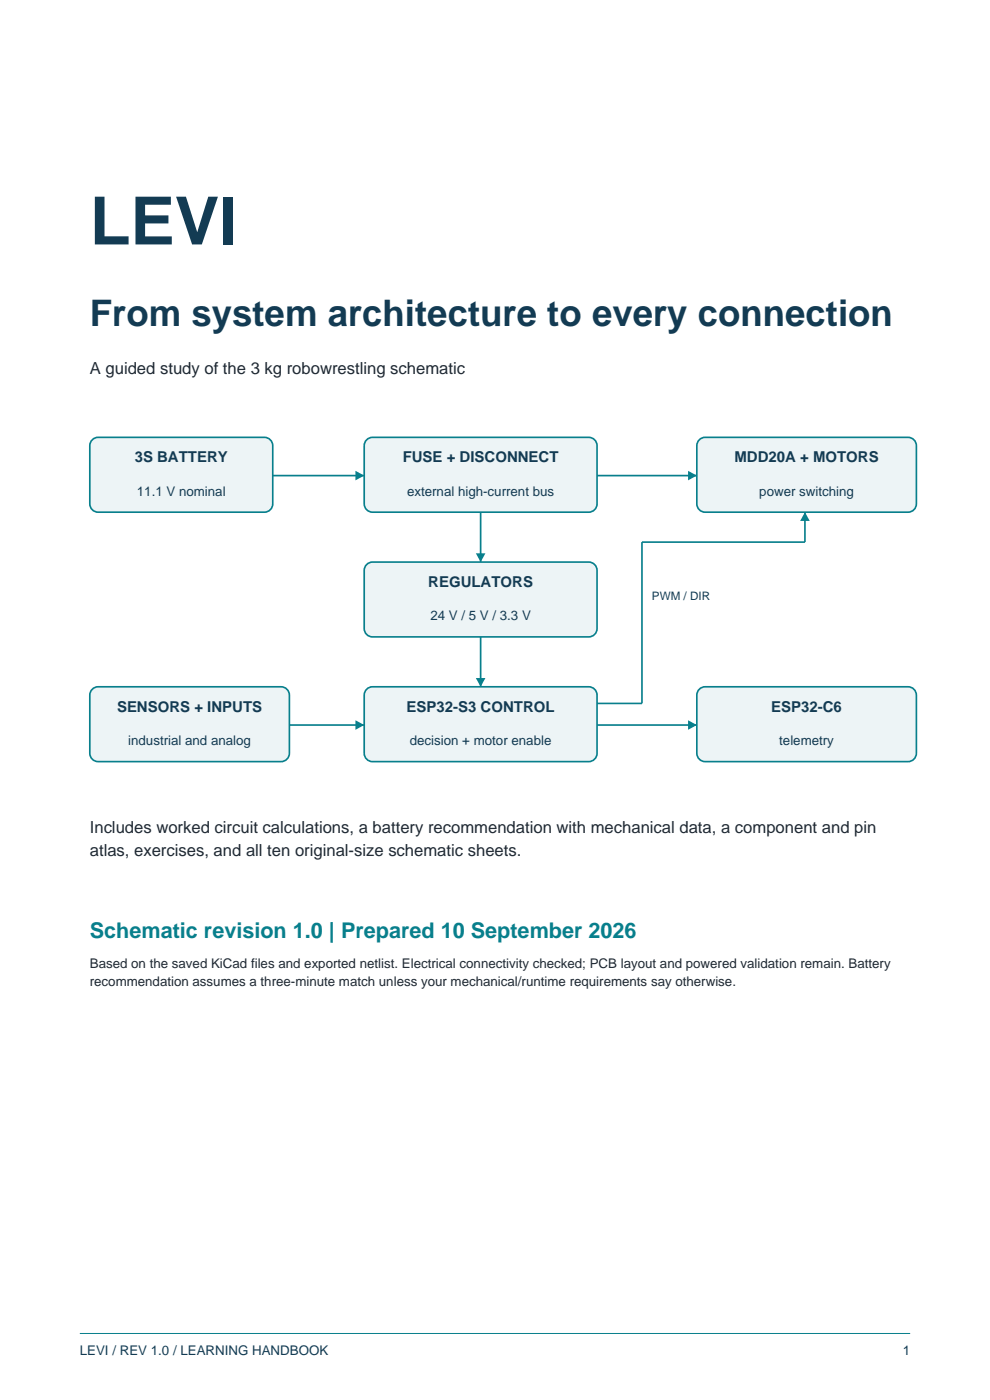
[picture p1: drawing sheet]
<svg xmlns="http://www.w3.org/2000/svg" width="210mm" height="297mm" viewBox="0 0 210 297" stroke-linecap="round" stroke-linejoin="round" font-family="sans-serif">
<defs><g id="words">
<text font-size="14.1" fill="#133b53" x="19" y="51.9">LEVI</text>
<text font-size="7.8" fill="#133b53" x="19" y="69.1">From system architecture to every connection</text>
<text font-size="4.6" fill="#087f8c" x="19" y="199">Schematic revision 1.0 | Prepared 10 September 2026</text>
<g font-size="3.5" fill="#1f2933">
<text x="19" y="79.4">A guided study of the 3 kg robowrestling schematic</text>
<text x="19" y="176.7">Includes worked circuit calculations, a battery recommendation with mechanical data, a component and pin</text>
<text x="19" y="181.7">atlas, exercises, and all ten original-size schematic sheets.</text>
</g>
<g font-size="3.2" fill="#133b53">
<text x="28.6" y="98.1">3S BATTERY</text>
<text x="85.4" y="98.1">FUSE + DISCONNECT</text>
<text x="155.8" y="98.1">MDD20A + MOTORS</text>
<text x="90.8" y="124.5">REGULATORS</text>
<text x="24.8" y="151">SENSORS + INPUTS</text>
<text x="86.3" y="151">ESP32-S3 CONTROL</text>
<text x="163.6" y="151">ESP32-C6</text>
</g>
<g font-size="2.8" fill="#133b53">
<text x="29" y="105.1">11.1 V nominal</text>
<text x="86.3" y="105.1">external high-current bus</text>
<text x="161.1" y="105.1">power switching</text>
<text x="91.3" y="131.6">24 V / 5 V / 3.3 V</text>
<text x="27.2" y="158">industrial and analog</text>
<text x="86.9" y="158">decision + motor enable</text>
<text x="165.3" y="158">telemetry</text>
<text x="16.9" y="287.5">LEVI / REV 1.0 / LEARNING HANDBOOK</text>
<text x="191.5" y="287.5">1</text>
</g>
<g font-size="2.8" fill="#1f2933">
<text x="19" y="205.3">Based on the saved KiCad files and exported netlist. Electrical connectivity checked; PCB layout and powered validation remain. Battery</text>
<text x="19" y="209.2">recommendation assumes a three-minute match unless your mechanical/runtime requirements say otherwise.</text>
</g>
<text font-size="2.5" fill="#133b53" x="138.3" y="127.4">PWM / DIR</text>
</g></defs>
<path d="M16.9 282.9h176.2" fill="none" stroke="#087f8c" stroke-width=".21"/>
<g fill="#edf4f6" stroke="#087f8c" stroke-width=".35">
<path d="M19.6 93.3l.7-.5h.5h35.3a1.76 1.76 0 0 1 1.8 1.7v12.4a1.76 1.76 0 0 1-1.8 1.8h-35.3a1.76 1.76 0 0 1-1.8-1.8v-12.4l.1-.4z" fill-rule="evenodd"/>
<path d="M77.8 93.3l.8-.5h.4h45.9a1.76 1.76 0 0 1 1.7 1.7v12.4a1.76 1.76 0 0 1-1.7 1.8h-45.9a1.76 1.76 0 0 1-1.7-1.8v-12.4v-.4z" fill-rule="evenodd"/>
<path d="M148.3 93.3l.8-.5h.5h43a1.76 1.76 0 0 1 1.8 1.7v12.4a1.76 1.76 0 0 1-1.8 1.8h-43a1.76 1.76 0 0 1-1.8-1.8v-12.4l.1-.4z" fill-rule="evenodd"/>
</g>
<path d="M57.9 100.9h19.4" fill="none" stroke="#087f8c" stroke-width=".35"/>
<path d="M75.4 99.9l1.9 1-1.9 1z" fill="#087f8c"/>
<path d="M126.6 100.9h21.2" fill="none" stroke="#087f8c" stroke-width=".35"/>
<path d="M146 99.9l1.8 1-1.8 1z" fill="#087f8c"/>
<path d="M77.8 119.8l.8-.5 .4-.1h45.9a1.76 1.76 0 0 1 1.7 1.8v12.3a1.76 1.76 0 0 1-1.7 1.8h-45.9a1.76 1.76 0 0 1-1.7-1.8v-12.3v-.5z" fill-rule="evenodd" fill="#edf4f6" stroke="#087f8c" stroke-width=".35"/>
<path d="M102 108.7v10.5" fill="none" stroke="#087f8c" stroke-width=".35"/>
<path d="M100.9 117.4h2.1l-1 1.8z" fill="#087f8c"/>
<g fill="#edf4f6" stroke="#087f8c" stroke-width=".35">
<path d="M19.6 146.2l.7-.4 .5-.1h38.8a1.76 1.76 0 0 1 1.8 1.8v12.3a1.76 1.76 0 0 1-1.8 1.8h-38.8a1.76 1.76 0 0 1-1.8-1.8v-12.3l.1-.5z" fill-rule="evenodd"/>
<path d="M77.8 146.2l.8-.4 .4-.1h45.9a1.76 1.76 0 0 1 1.7 1.8v12.3a1.76 1.76 0 0 1-1.7 1.8h-45.9a1.76 1.76 0 0 1-1.7-1.8v-12.3v-.5z" fill-rule="evenodd"/>
<path d="M148.3 146.2l.8-.4 .5-.1h43a1.76 1.76 0 0 1 1.8 1.8v12.3a1.76 1.76 0 0 1-1.8 1.8h-43a1.76 1.76 0 0 1-1.8-1.8v-12.3l.1-.5z" fill-rule="evenodd"/>
</g>
<path d="M61.4 153.8h15.9" fill="none" stroke="#087f8c" stroke-width=".35"/>
<path d="M75.4 152.8l1.9 1-1.9 1z" fill="#087f8c"/>
<path d="M126.6 153.8h21.2" fill="none" stroke="#087f8c" stroke-width=".35"/>
<path d="M146 152.8l1.8 1-1.8 1z" fill="#087f8c"/>
<path d="M102 135.1v10.6" fill="none" stroke="#087f8c" stroke-width=".35"/>
<path d="M100.9 143.8h2.1l-1 1.9z" fill="#087f8c"/>
<path d="M170.7 108.7v6.3h-34.5v34.2h-9.6" fill="none" stroke="#087f8c" stroke-width=".35"/>
<path d="M170.7 108.7l1.1 1.8h-2.1z" fill="#087f8c"/>
<use href="#words"/>
</svg>
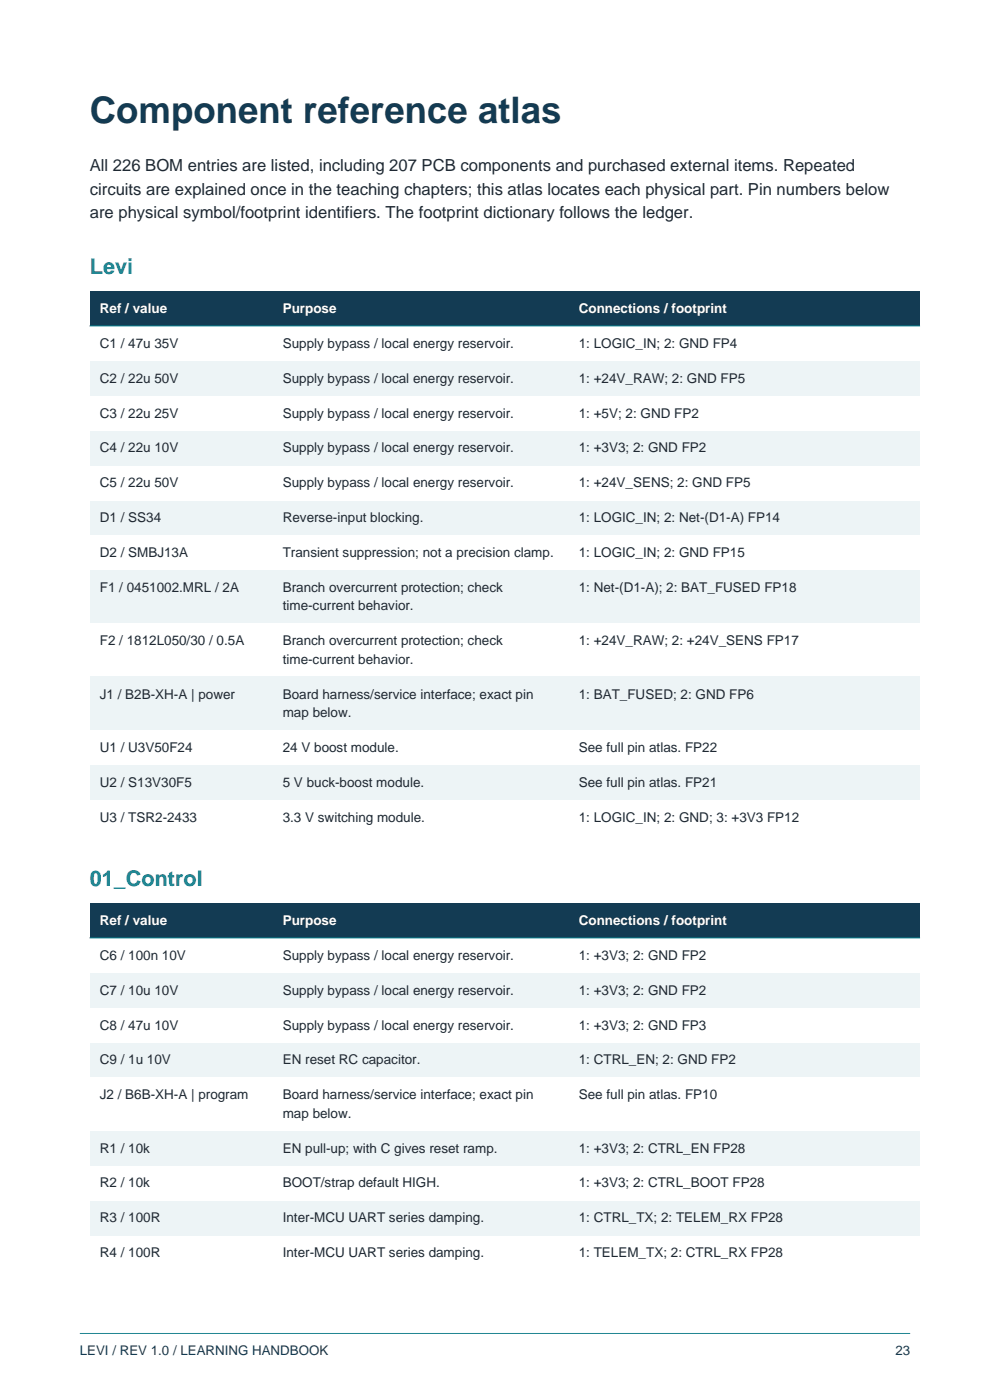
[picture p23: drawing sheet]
<svg xmlns="http://www.w3.org/2000/svg" width="210mm" height="297mm" viewBox="0 0 210 297" stroke-linecap="round" stroke-linejoin="round" font-family="sans-serif">
<defs><g id="words">
<text font-size="7.8" fill="#133b53" x="19" y="26.1">Component reference atlas</text>
<g font-size="4.6" fill="#087f8c">
<text x="19" y="58.2">Levi</text>
<text x="19" y="188">01_Control</text>
</g>
<g font-size="3.5" fill="#1f2933">
<text x="19" y="36.3">All 226 BOM entries are listed, including 207 PCB components and purchased external items. Repeated</text>
<text x="19" y="41.3">circuits are explained once in the teaching chapters; this atlas locates each physical part. Pin numbers below</text>
<text x="19" y="46.2">are physical symbol/footprint identifiers. The footprint dictionary follows the ledger.</text>
</g>
<g font-size="2.9" fill="#fff">
<text x="21.2" y="66.4">Ref / value</text>
<text x="60" y="66.4">Purpose</text>
<text x="122.8" y="66.4">Connections / footprint</text>
<text x="21.2" y="196.2">Ref / value</text>
<text x="60" y="196.2">Purpose</text>
<text x="122.8" y="196.2">Connections / footprint</text>
</g>
<g font-size="2.9" fill="#1f2933">
<text x="21.2" y="73.8">C1 / 47u 35V</text>
<text x="60" y="73.8">Supply bypass / local energy reservoir.</text>
<text x="122.8" y="73.8">1: LOGIC_IN; 2: GND FP4</text>
<text x="21.2" y="81.2">C2 / 22u 50V</text>
<text x="60" y="81.2">Supply bypass / local energy reservoir.</text>
<text x="122.8" y="81.2">1: +24V_RAW; 2: GND FP5</text>
<text x="21.2" y="88.6">C3 / 22u 25V</text>
<text x="60" y="88.6">Supply bypass / local energy reservoir.</text>
<text x="122.8" y="88.6">1: +5V; 2: GND FP2</text>
<text x="21.2" y="96">C4 / 22u 10V</text>
<text x="60" y="96">Supply bypass / local energy reservoir.</text>
<text x="122.8" y="96">1: +3V3; 2: GND FP2</text>
<text x="21.2" y="103.4">C5 / 22u 50V</text>
<text x="60" y="103.4">Supply bypass / local energy reservoir.</text>
<text x="122.8" y="103.4">1: +24V_SENS; 2: GND FP5</text>
<text x="21.2" y="110.8">D1 / SS34</text>
<text x="60" y="110.8">Reverse-input blocking.</text>
<text x="122.8" y="110.8">1: LOGIC_IN; 2: Net-(D1-A) FP14</text>
<text x="21.2" y="118.2">D2 / SMBJ13A</text>
<text x="60" y="118.2">Transient suppression; not a precision clamp.</text>
<text x="122.8" y="118.2">1: LOGIC_IN; 2: GND FP15</text>
<text x="21.2" y="125.6">F1 / 0451002.MRL / 2A</text>
<text x="60" y="125.6">Branch overcurrent protection; check</text>
<text x="122.8" y="125.6">1: Net-(D1-A); 2: BAT_FUSED FP18</text>
<text x="60" y="129.5">time-current behavior.</text>
<text x="21.2" y="136.9">F2 / 1812L050/30 / 0.5A</text>
<text x="60" y="136.9">Branch overcurrent protection; check</text>
<text x="122.8" y="136.9">1: +24V_RAW; 2: +24V_SENS FP17</text>
<text x="60" y="140.8">time-current behavior.</text>
<text x="21.2" y="148.2">J1 / B2B-XH-A | power</text>
<text x="60" y="148.2">Board harness/service interface; exact pin</text>
<text x="122.8" y="148.2">1: BAT_FUSED; 2: GND FP6</text>
<text x="60" y="152.1">map below.</text>
<text x="21.2" y="159.5">U1 / U3V50F24</text>
<text x="60" y="159.5">24 V boost module.</text>
<text x="122.8" y="159.5">See full pin atlas. FP22</text>
<text x="21.2" y="166.9">U2 / S13V30F5</text>
<text x="60" y="166.9">5 V buck-boost module.</text>
<text x="122.8" y="166.9">See full pin atlas. FP21</text>
<text x="21.2" y="174.3">U3 / TSR2-2433</text>
<text x="60" y="174.3">3.3 V switching module.</text>
<text x="122.8" y="174.3">1: LOGIC_IN; 2: GND; 3: +3V3 FP12</text>
<text x="21.2" y="203.6">C6 / 100n 10V</text>
<text x="60" y="203.6">Supply bypass / local energy reservoir.</text>
<text x="122.8" y="203.6">1: +3V3; 2: GND FP2</text>
<text x="21.2" y="211">C7 / 10u 10V</text>
<text x="60" y="211">Supply bypass / local energy reservoir.</text>
<text x="122.8" y="211">1: +3V3; 2: GND FP2</text>
<text x="21.2" y="218.4">C8 / 47u 10V</text>
<text x="60" y="218.4">Supply bypass / local energy reservoir.</text>
<text x="122.8" y="218.4">1: +3V3; 2: GND FP3</text>
<text x="21.2" y="225.8">C9 / 1u 10V</text>
<text x="60" y="225.8">EN reset RC capacitor.</text>
<text x="122.8" y="225.8">1: CTRL_EN; 2: GND FP2</text>
<text x="21.2" y="233.2">J2 / B6B-XH-A | program</text>
<text x="60" y="233.2">Board harness/service interface; exact pin</text>
<text x="122.8" y="233.2">See full pin atlas. FP10</text>
<text x="60" y="237.1">map below.</text>
<text x="21.2" y="244.5">R1 / 10k</text>
<text x="60" y="244.5">EN pull-up; with C gives reset ramp.</text>
<text x="122.8" y="244.5">1: +3V3; 2: CTRL_EN FP28</text>
<text x="21.2" y="251.9">R2 / 10k</text>
<text x="60" y="251.9">BOOT/strap default HIGH.</text>
<text x="122.8" y="251.9">1: +3V3; 2: CTRL_BOOT FP28</text>
<text x="21.2" y="259.3">R3 / 100R</text>
<text x="60" y="259.3">Inter-MCU UART series damping.</text>
<text x="122.8" y="259.3">1: CTRL_TX; 2: TELEM_RX FP28</text>
<text x="21.2" y="266.7">R4 / 100R</text>
<text x="60" y="266.7">Inter-MCU UART series damping.</text>
<text x="122.8" y="266.7">1: TELEM_TX; 2: CTRL_RX FP28</text>
</g>
<g font-size="2.8" fill="#133b53">
<text x="16.9" y="287.5">LEVI / REV 1.0 / LEARNING HANDBOOK</text>
<text x="189.9" y="287.5">23</text>
</g>
</g></defs>
<path d="M16.9 282.9h176.2" fill="none" stroke="#087f8c" stroke-width=".21"/>
<path d="M19 61.7h176.1v7.4h-176.1z" fill-rule="evenodd" fill="#133b53"/>
<path d="M19 69.1h176.1v7.5h-176.1z" fill-rule="evenodd" fill="#fff"/>
<path d="M19 76.6h176.1v7.4h-176.1z" fill-rule="evenodd" fill="#edf4f6"/>
<path d="M19 84h176.1v7.4h-176.1z" fill-rule="evenodd" fill="#fff"/>
<path d="M19 91.4h176.1v7.4h-176.1z" fill-rule="evenodd" fill="#edf4f6"/>
<path d="M19 98.8h176.1v7.4h-176.1z" fill-rule="evenodd" fill="#fff"/>
<path d="M19 106.2h176.1v7.4h-176.1z" fill-rule="evenodd" fill="#edf4f6"/>
<path d="M19 113.6h176.1v7.4h-176.1z" fill-rule="evenodd" fill="#fff"/>
<path d="M19 121h176.1v11.3h-176.1z" fill-rule="evenodd" fill="#edf4f6"/>
<path d="M19 132.3h176.1v11.3h-176.1z" fill-rule="evenodd" fill="#fff"/>
<path d="M19 143.6h176.1v11.3h-176.1z" fill-rule="evenodd" fill="#edf4f6"/>
<path d="M19 154.9h176.1v7.4h-176.1z" fill-rule="evenodd" fill="#fff"/>
<path d="M19 162.3h176.1v7.4h-176.1z" fill-rule="evenodd" fill="#edf4f6"/>
<path d="M19 169.7h176.1v7.4h-176.1z" fill-rule="evenodd" fill="#fff"/>
<path d="M19 69.1h176.1" fill="none" stroke="#087f8c" stroke-width=".21"/>
<path d="M19 191.6h176.1v7.4h-176.1z" fill-rule="evenodd" fill="#133b53"/>
<path d="M19 199h176.1v7.4h-176.1z" fill-rule="evenodd" fill="#fff"/>
<path d="M19 206.4h176.1v7.4h-176.1z" fill-rule="evenodd" fill="#edf4f6"/>
<path d="M19 213.8h176.1v7.4h-176.1z" fill-rule="evenodd" fill="#fff"/>
<path d="M19 221.2h176.1v7.4h-176.1z" fill-rule="evenodd" fill="#edf4f6"/>
<path d="M19 228.6h176.1v11.3h-176.1z" fill-rule="evenodd" fill="#fff"/>
<path d="M19 239.9h176.1v7.4h-176.1z" fill-rule="evenodd" fill="#edf4f6"/>
<path d="M19 247.3h176.1v7.4h-176.1z" fill-rule="evenodd" fill="#fff"/>
<path d="M19 254.7h176.1v7.4h-176.1z" fill-rule="evenodd" fill="#edf4f6"/>
<path d="M19 262.1h176.1v7.4h-176.1z" fill-rule="evenodd" fill="#fff"/>
<path d="M19 199h176.1" fill="none" stroke="#087f8c" stroke-width=".21"/>
<use href="#words"/>
</svg>
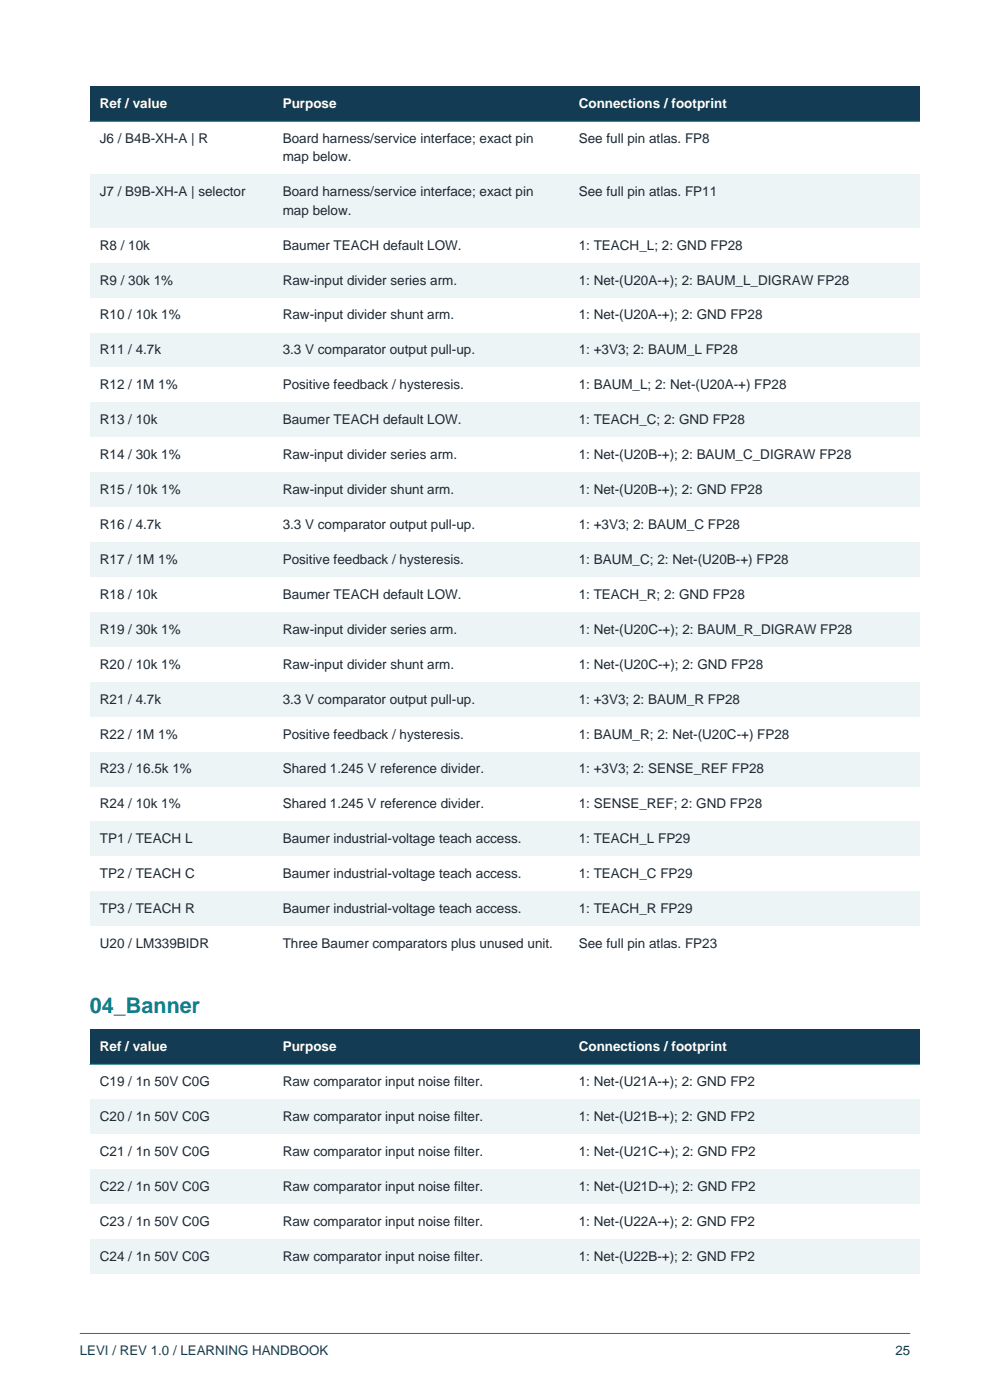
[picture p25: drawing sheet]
<svg xmlns="http://www.w3.org/2000/svg" width="210mm" height="297mm" viewBox="0 0 210 297" stroke-linecap="round" stroke-linejoin="round" font-family="sans-serif">
<defs><g id="words">
<text font-size="4.6" fill="#087f8c" x="19" y="214.8">04_Banner</text>
<g font-size="2.9" fill="#fff">
<text x="21.2" y="23">Ref / value</text>
<text x="60" y="23">Purpose</text>
<text x="122.8" y="23">Connections / footprint</text>
<text x="21.2" y="223">Ref / value</text>
<text x="60" y="223">Purpose</text>
<text x="122.8" y="223">Connections / footprint</text>
</g>
<g font-size="2.9" fill="#1f2933">
<text x="21.2" y="30.4">J6 / B4B-XH-A | R</text>
<text x="60" y="30.4">Board harness/service interface; exact pin</text>
<text x="60" y="34.3">map below.</text>
<text x="122.8" y="30.4">See full pin atlas. FP8</text>
<text x="21.2" y="41.7">J7 / B9B-XH-A | selector</text>
<text x="60" y="41.7">Board harness/service interface; exact pin</text>
<text x="122.8" y="41.7">See full pin atlas. FP11</text>
<text x="60" y="45.5">map below.</text>
<text x="21.2" y="53">R8 / 10k</text>
<text x="60" y="53">Baumer TEACH default LOW.</text>
<text x="122.8" y="53">1: TEACH_L; 2: GND FP28</text>
<text x="21.2" y="60.4">R9 / 30k 1%</text>
<text x="60" y="60.4">Raw-input divider series arm.</text>
<text x="122.8" y="60.4">1: Net-(U20A-+); 2: BAUM_L_DIGRAW FP28</text>
<text x="21.2" y="67.8">R10 / 10k 1%</text>
<text x="60" y="67.8">Raw-input divider shunt arm.</text>
<text x="122.8" y="67.8">1: Net-(U20A-+); 2: GND FP28</text>
<text x="21.2" y="75.2">R11 / 4.7k</text>
<text x="60" y="75.2">3.3 V comparator output pull-up.</text>
<text x="122.8" y="75.2">1: +3V3; 2: BAUM_L FP28</text>
<text x="21.2" y="82.6">R12 / 1M 1%</text>
<text x="60" y="82.6">Positive feedback / hysteresis.</text>
<text x="122.8" y="82.6">1: BAUM_L; 2: Net-(U20A-+) FP28</text>
<text x="21.2" y="90">R13 / 10k</text>
<text x="60" y="90">Baumer TEACH default LOW.</text>
<text x="122.8" y="90">1: TEACH_C; 2: GND FP28</text>
<text x="21.2" y="97.4">R14 / 30k 1%</text>
<text x="60" y="97.4">Raw-input divider series arm.</text>
<text x="122.8" y="97.4">1: Net-(U20B-+); 2: BAUM_C_DIGRAW FP28</text>
<text x="21.2" y="104.8">R15 / 10k 1%</text>
<text x="60" y="104.8">Raw-input divider shunt arm.</text>
<text x="122.8" y="104.8">1: Net-(U20B-+); 2: GND FP28</text>
<text x="21.2" y="112.2">R16 / 4.7k</text>
<text x="60" y="112.2">3.3 V comparator output pull-up.</text>
<text x="122.8" y="112.2">1: +3V3; 2: BAUM_C FP28</text>
<text x="21.2" y="119.6">R17 / 1M 1%</text>
<text x="60" y="119.6">Positive feedback / hysteresis.</text>
<text x="122.8" y="119.6">1: BAUM_C; 2: Net-(U20B-+) FP28</text>
<text x="21.2" y="127">R18 / 10k</text>
<text x="60" y="127">Baumer TEACH default LOW.</text>
<text x="122.8" y="127">1: TEACH_R; 2: GND FP28</text>
<text x="21.2" y="134.4">R19 / 30k 1%</text>
<text x="60" y="134.4">Raw-input divider series arm.</text>
<text x="122.8" y="134.4">1: Net-(U20C-+); 2: BAUM_R_DIGRAW FP28</text>
<text x="21.2" y="141.9">R20 / 10k 1%</text>
<text x="60" y="141.9">Raw-input divider shunt arm.</text>
<text x="122.8" y="141.9">1: Net-(U20C-+); 2: GND FP28</text>
<text x="21.2" y="149.3">R21 / 4.7k</text>
<text x="60" y="149.3">3.3 V comparator output pull-up.</text>
<text x="122.8" y="149.3">1: +3V3; 2: BAUM_R FP28</text>
<text x="21.2" y="156.7">R22 / 1M 1%</text>
<text x="60" y="156.7">Positive feedback / hysteresis.</text>
<text x="122.8" y="156.7">1: BAUM_R; 2: Net-(U20C-+) FP28</text>
<text x="21.2" y="164.1">R23 / 16.5k 1%</text>
<text x="60" y="164.1">Shared 1.245 V reference divider.</text>
<text x="122.8" y="164.1">1: +3V3; 2: SENSE_REF FP28</text>
<text x="21.2" y="171.5">R24 / 10k 1%</text>
<text x="60" y="171.5">Shared 1.245 V reference divider.</text>
<text x="122.8" y="171.5">1: SENSE_REF; 2: GND FP28</text>
<text x="21.2" y="178.9">TP1 / TEACH L</text>
<text x="60" y="178.9">Baumer industrial-voltage teach access.</text>
<text x="122.8" y="178.9">1: TEACH_L FP29</text>
<text x="21.2" y="186.3">TP2 / TEACH C</text>
<text x="60" y="186.3">Baumer industrial-voltage teach access.</text>
<text x="122.8" y="186.3">1: TEACH_C FP29</text>
<text x="21.2" y="193.7">TP3 / TEACH R</text>
<text x="60" y="193.7">Baumer industrial-voltage teach access.</text>
<text x="122.8" y="193.7">1: TEACH_R FP29</text>
<text x="21.2" y="201.1">U20 / LM339BIDR</text>
<text x="60" y="201.1">Three Baumer comparators plus unused unit.</text>
<text x="122.8" y="201.1">See full pin atlas. FP23</text>
<text x="21.2" y="230.4">C19 / 1n 50V C0G</text>
<text x="60" y="230.4">Raw comparator input noise filter.</text>
<text x="122.8" y="230.4">1: Net-(U21A-+); 2: GND FP2</text>
<text x="21.2" y="237.8">C20 / 1n 50V C0G</text>
<text x="60" y="237.8">Raw comparator input noise filter.</text>
<text x="122.8" y="237.8">1: Net-(U21B-+); 2: GND FP2</text>
<text x="21.2" y="245.2">C21 / 1n 50V C0G</text>
<text x="60" y="245.2">Raw comparator input noise filter.</text>
<text x="122.8" y="245.2">1: Net-(U21C-+); 2: GND FP2</text>
<text x="21.2" y="252.6">C22 / 1n 50V C0G</text>
<text x="60" y="252.6">Raw comparator input noise filter.</text>
<text x="122.8" y="252.6">1: Net-(U21D-+); 2: GND FP2</text>
<text x="21.2" y="260">C23 / 1n 50V C0G</text>
<text x="60" y="260">Raw comparator input noise filter.</text>
<text x="122.8" y="260">1: Net-(U22A-+); 2: GND FP2</text>
<text x="21.2" y="267.4">C24 / 1n 50V C0G</text>
<text x="60" y="267.4">Raw comparator input noise filter.</text>
<text x="122.8" y="267.4">1: Net-(U22B-+); 2: GND FP2</text>
</g>
<g font-size="2.8" fill="#133b53">
<text x="16.9" y="287.5">LEVI / REV 1.0 / LEARNING HANDBOOK</text>
<text x="189.9" y="287.5">25</text>
</g>
</g></defs>
<path d="M16.9 282.9h176.2" fill="none" stroke="#087f8c" stroke-width=".21"/>
<path d="M19 18.3h176.1v7.5h-176.1z" fill-rule="evenodd" fill="#133b53"/>
<path d="M19 25.8h176.1v11.2h-176.1z" fill-rule="evenodd" fill="#fff"/>
<path d="M19 37h176.1v11.3h-176.1z" fill-rule="evenodd" fill="#edf4f6"/>
<path d="M19 48.3h176.1v7.4h-176.1z" fill-rule="evenodd" fill="#fff"/>
<path d="M19 55.7h176.1v7.4h-176.1z" fill-rule="evenodd" fill="#edf4f6"/>
<path d="M19 63.1h176.1v7.5h-176.1z" fill-rule="evenodd" fill="#fff"/>
<path d="M19 70.6h176.1v7.4h-176.1z" fill-rule="evenodd" fill="#edf4f6"/>
<path d="M19 78h176.1v7.4h-176.1z" fill-rule="evenodd" fill="#fff"/>
<path d="M19 85.4h176.1v7.4h-176.1z" fill-rule="evenodd" fill="#edf4f6"/>
<path d="M19 92.8h176.1v7.4h-176.1z" fill-rule="evenodd" fill="#fff"/>
<path d="M19 100.2h176.1v7.4h-176.1z" fill-rule="evenodd" fill="#edf4f6"/>
<path d="M19 107.6h176.1v7.4h-176.1z" fill-rule="evenodd" fill="#fff"/>
<path d="M19 115h176.1v7.4h-176.1z" fill-rule="evenodd" fill="#edf4f6"/>
<path d="M19 122.4h176.1v7.4h-176.1z" fill-rule="evenodd" fill="#fff"/>
<path d="M19 129.8h176.1v7.4h-176.1z" fill-rule="evenodd" fill="#edf4f6"/>
<path d="M19 137.2h176.1v7.4h-176.1z" fill-rule="evenodd" fill="#fff"/>
<path d="M19 144.6h176.1v7.4h-176.1z" fill-rule="evenodd" fill="#edf4f6"/>
<path d="M19 152h176.1v7.5h-176.1z" fill-rule="evenodd" fill="#fff"/>
<path d="M19 159.5h176.1v7.4h-176.1z" fill-rule="evenodd" fill="#edf4f6"/>
<path d="M19 166.9h176.1v7.4h-176.1z" fill-rule="evenodd" fill="#fff"/>
<path d="M19 174.3h176.1v7.4h-176.1z" fill-rule="evenodd" fill="#edf4f6"/>
<path d="M19 181.7h176.1v7.4h-176.1z" fill-rule="evenodd" fill="#fff"/>
<path d="M19 189.1h176.1v7.4h-176.1z" fill-rule="evenodd" fill="#edf4f6"/>
<path d="M19 196.5h176.1v7.4h-176.1z" fill-rule="evenodd" fill="#fff"/>
<path d="M19 25.8h176.1" fill="none" stroke="#087f8c" stroke-width=".21"/>
<path d="M19 218.4h176.1v7.4h-176.1z" fill-rule="evenodd" fill="#133b53"/>
<path d="M19 225.8h176.1v7.4h-176.1z" fill-rule="evenodd" fill="#fff"/>
<path d="M19 233.2h176.1v7.4h-176.1z" fill-rule="evenodd" fill="#edf4f6"/>
<path d="M19 240.6h176.1v7.4h-176.1z" fill-rule="evenodd" fill="#fff"/>
<path d="M19 248h176.1v7.4h-176.1z" fill-rule="evenodd" fill="#edf4f6"/>
<path d="M19 255.4h176.1v7.4h-176.1z" fill-rule="evenodd" fill="#fff"/>
<path d="M19 262.8h176.1v7.4h-176.1z" fill-rule="evenodd" fill="#edf4f6"/>
<path d="M19 225.8h176.1" fill="none" stroke="#087f8c" stroke-width=".21"/>
<use href="#words"/>
</svg>
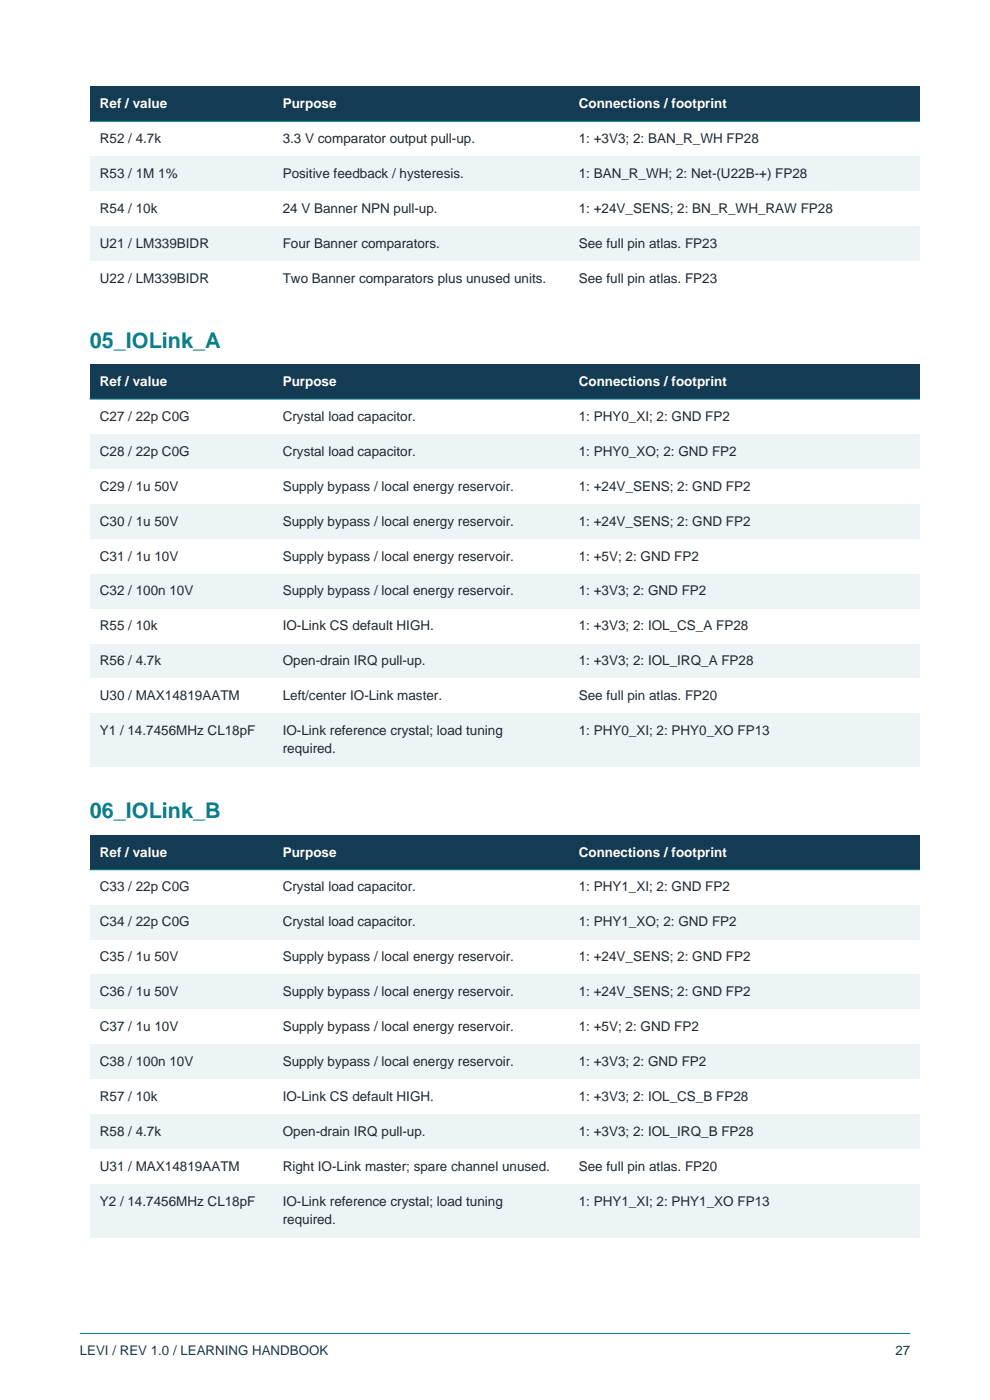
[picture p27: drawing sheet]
<svg xmlns="http://www.w3.org/2000/svg" width="210mm" height="297mm" viewBox="0 0 210 297" stroke-linecap="round" stroke-linejoin="round" font-family="sans-serif">
<defs><g id="words">
<g font-size="4.6" fill="#087f8c">
<text x="19" y="73.7">05_IOLink_A</text>
<text x="19" y="173.6">06_IOLink_B</text>
</g>
<g font-size="2.9" fill="#fff">
<text x="21.2" y="23">Ref / value</text>
<text x="60" y="23">Purpose</text>
<text x="122.8" y="23">Connections / footprint</text>
<text x="21.2" y="81.9">Ref / value</text>
<text x="60" y="81.9">Purpose</text>
<text x="122.8" y="81.9">Connections / footprint</text>
<text x="21.2" y="181.7">Ref / value</text>
<text x="60" y="181.7">Purpose</text>
<text x="122.8" y="181.7">Connections / footprint</text>
</g>
<g font-size="2.9" fill="#1f2933">
<text x="21.2" y="30.4">R52 / 4.7k</text>
<text x="60" y="30.4">3.3 V comparator output pull-up.</text>
<text x="122.8" y="30.4">1: +3V3; 2: BAN_R_WH FP28</text>
<text x="21.2" y="37.8">R53 / 1M 1%</text>
<text x="60" y="37.8">Positive feedback / hysteresis.</text>
<text x="122.8" y="37.8">1: BAN_R_WH; 2: Net-(U22B-+) FP28</text>
<text x="21.2" y="45.2">R54 / 10k</text>
<text x="60" y="45.2">24 V Banner NPN pull-up.</text>
<text x="122.8" y="45.2">1: +24V_SENS; 2: BN_R_WH_RAW FP28</text>
<text x="21.2" y="52.6">U21 / LM339BIDR</text>
<text x="60" y="52.6">Four Banner comparators.</text>
<text x="122.8" y="52.6">See full pin atlas. FP23</text>
<text x="21.2" y="60">U22 / LM339BIDR</text>
<text x="60" y="60">Two Banner comparators plus unused units.</text>
<text x="122.8" y="60">See full pin atlas. FP23</text>
<text x="21.2" y="89.3">C27 / 22p C0G</text>
<text x="60" y="89.3">Crystal load capacitor.</text>
<text x="122.8" y="89.3">1: PHY0_XI; 2: GND FP2</text>
<text x="21.2" y="96.7">C28 / 22p C0G</text>
<text x="60" y="96.7">Crystal load capacitor.</text>
<text x="122.8" y="96.7">1: PHY0_XO; 2: GND FP2</text>
<text x="21.2" y="104.1">C29 / 1u 50V</text>
<text x="60" y="104.1">Supply bypass / local energy reservoir.</text>
<text x="122.8" y="104.1">1: +24V_SENS; 2: GND FP2</text>
<text x="21.2" y="111.5">C30 / 1u 50V</text>
<text x="60" y="111.5">Supply bypass / local energy reservoir.</text>
<text x="122.8" y="111.5">1: +24V_SENS; 2: GND FP2</text>
<text x="21.2" y="118.9">C31 / 1u 10V</text>
<text x="60" y="118.9">Supply bypass / local energy reservoir.</text>
<text x="122.8" y="118.9">1: +5V; 2: GND FP2</text>
<text x="21.2" y="126.3">C32 / 100n 10V</text>
<text x="60" y="126.3">Supply bypass / local energy reservoir.</text>
<text x="122.8" y="126.3">1: +3V3; 2: GND FP2</text>
<text x="21.2" y="133.7">R55 / 10k</text>
<text x="60" y="133.7">IO-Link CS default HIGH.</text>
<text x="122.8" y="133.7">1: +3V3; 2: IOL_CS_A FP28</text>
<text x="21.2" y="141.1">R56 / 4.7k</text>
<text x="60" y="141.1">Open-drain IRQ pull-up.</text>
<text x="122.8" y="141.1">1: +3V3; 2: IOL_IRQ_A FP28</text>
<text x="21.2" y="148.6">U30 / MAX14819AATM</text>
<text x="60" y="148.6">Left/center IO-Link master.</text>
<text x="122.8" y="148.6">See full pin atlas. FP20</text>
<text x="21.2" y="156">Y1 / 14.7456MHz CL18pF</text>
<text x="60" y="156">IO-Link reference crystal; load tuning</text>
<text x="122.8" y="156">1: PHY0_XI; 2: PHY0_XO FP13</text>
<text x="60" y="159.8">required.</text>
<text x="21.2" y="189.1">C33 / 22p C0G</text>
<text x="60" y="189.1">Crystal load capacitor.</text>
<text x="122.8" y="189.1">1: PHY1_XI; 2: GND FP2</text>
<text x="21.2" y="196.5">C34 / 22p C0G</text>
<text x="60" y="196.5">Crystal load capacitor.</text>
<text x="122.8" y="196.5">1: PHY1_XO; 2: GND FP2</text>
<text x="21.2" y="203.9">C35 / 1u 50V</text>
<text x="60" y="203.9">Supply bypass / local energy reservoir.</text>
<text x="122.8" y="203.9">1: +24V_SENS; 2: GND FP2</text>
<text x="21.2" y="211.3">C36 / 1u 50V</text>
<text x="60" y="211.3">Supply bypass / local energy reservoir.</text>
<text x="122.8" y="211.3">1: +24V_SENS; 2: GND FP2</text>
<text x="21.2" y="218.8">C37 / 1u 10V</text>
<text x="60" y="218.8">Supply bypass / local energy reservoir.</text>
<text x="122.8" y="218.8">1: +5V; 2: GND FP2</text>
<text x="21.2" y="226.2">C38 / 100n 10V</text>
<text x="60" y="226.2">Supply bypass / local energy reservoir.</text>
<text x="122.8" y="226.2">1: +3V3; 2: GND FP2</text>
<text x="21.2" y="233.6">R57 / 10k</text>
<text x="60" y="233.6">IO-Link CS default HIGH.</text>
<text x="122.8" y="233.6">1: +3V3; 2: IOL_CS_B FP28</text>
<text x="21.2" y="241">R58 / 4.7k</text>
<text x="60" y="241">Open-drain IRQ pull-up.</text>
<text x="122.8" y="241">1: +3V3; 2: IOL_IRQ_B FP28</text>
<text x="21.2" y="248.4">U31 / MAX14819AATM</text>
<text x="60" y="248.4">Right IO-Link master; spare channel unused.</text>
<text x="122.8" y="248.4">See full pin atlas. FP20</text>
<text x="21.2" y="255.8">Y2 / 14.7456MHz CL18pF</text>
<text x="60" y="255.8">IO-Link reference crystal; load tuning</text>
<text x="122.8" y="255.8">1: PHY1_XI; 2: PHY1_XO FP13</text>
<text x="60" y="259.7">required.</text>
</g>
<g font-size="2.8" fill="#133b53">
<text x="16.9" y="287.5">LEVI / REV 1.0 / LEARNING HANDBOOK</text>
<text x="189.9" y="287.5">27</text>
</g>
</g></defs>
<path d="M16.9 282.9h176.2" fill="none" stroke="#087f8c" stroke-width=".21"/>
<path d="M19 18.3h176.1v7.5h-176.1z" fill-rule="evenodd" fill="#133b53"/>
<path d="M19 25.8h176.1v7.4h-176.1z" fill-rule="evenodd" fill="#fff"/>
<path d="M19 33.2h176.1v7.4h-176.1z" fill-rule="evenodd" fill="#edf4f6"/>
<path d="M19 40.6h176.1v7.4h-176.1z" fill-rule="evenodd" fill="#fff"/>
<path d="M19 48h176.1v7.4h-176.1z" fill-rule="evenodd" fill="#edf4f6"/>
<path d="M19 55.4h176.1v7.4h-176.1z" fill-rule="evenodd" fill="#fff"/>
<path d="M19 25.8h176.1" fill="none" stroke="#087f8c" stroke-width=".21"/>
<path d="M19 77.3h176.1v7.4h-176.1z" fill-rule="evenodd" fill="#133b53"/>
<path d="M19 84.7h176.1v7.4h-176.1z" fill-rule="evenodd" fill="#fff"/>
<path d="M19 92.1h176.1v7.4h-176.1z" fill-rule="evenodd" fill="#edf4f6"/>
<path d="M19 99.5h176.1v7.4h-176.1z" fill-rule="evenodd" fill="#fff"/>
<path d="M19 106.9h176.1v7.4h-176.1z" fill-rule="evenodd" fill="#edf4f6"/>
<path d="M19 114.3h176.1v7.4h-176.1z" fill-rule="evenodd" fill="#fff"/>
<path d="M19 121.7h176.1v7.4h-176.1z" fill-rule="evenodd" fill="#edf4f6"/>
<path d="M19 129.1h176.1v7.4h-176.1z" fill-rule="evenodd" fill="#fff"/>
<path d="M19 136.5h176.1v7.4h-176.1z" fill-rule="evenodd" fill="#edf4f6"/>
<path d="M19 143.9h176.1v7.4h-176.1z" fill-rule="evenodd" fill="#fff"/>
<path d="M19 151.3h176.1v11.3h-176.1z" fill-rule="evenodd" fill="#edf4f6"/>
<path d="M19 84.7h176.1" fill="none" stroke="#087f8c" stroke-width=".21"/>
<path d="M19 177.1h176.1v7.4h-176.1z" fill-rule="evenodd" fill="#133b53"/>
<path d="M19 184.5h176.1v7.4h-176.1z" fill-rule="evenodd" fill="#fff"/>
<path d="M19 191.9h176.1v7.4h-176.1z" fill-rule="evenodd" fill="#edf4f6"/>
<path d="M19 199.3h176.1v7.4h-176.1z" fill-rule="evenodd" fill="#fff"/>
<path d="M19 206.7h176.1v7.4h-176.1z" fill-rule="evenodd" fill="#edf4f6"/>
<path d="M19 214.1h176.1v7.4h-176.1z" fill-rule="evenodd" fill="#fff"/>
<path d="M19 221.5h176.1v7.5h-176.1z" fill-rule="evenodd" fill="#edf4f6"/>
<path d="M19 229h176.1v7.4h-176.1z" fill-rule="evenodd" fill="#fff"/>
<path d="M19 236.4h176.1v7.4h-176.1z" fill-rule="evenodd" fill="#edf4f6"/>
<path d="M19 243.8h176.1v7.4h-176.1z" fill-rule="evenodd" fill="#fff"/>
<path d="M19 251.2h176.1v11.3h-176.1z" fill-rule="evenodd" fill="#edf4f6"/>
<path d="M19 184.5h176.1" fill="none" stroke="#087f8c" stroke-width=".21"/>
<use href="#words"/>
</svg>
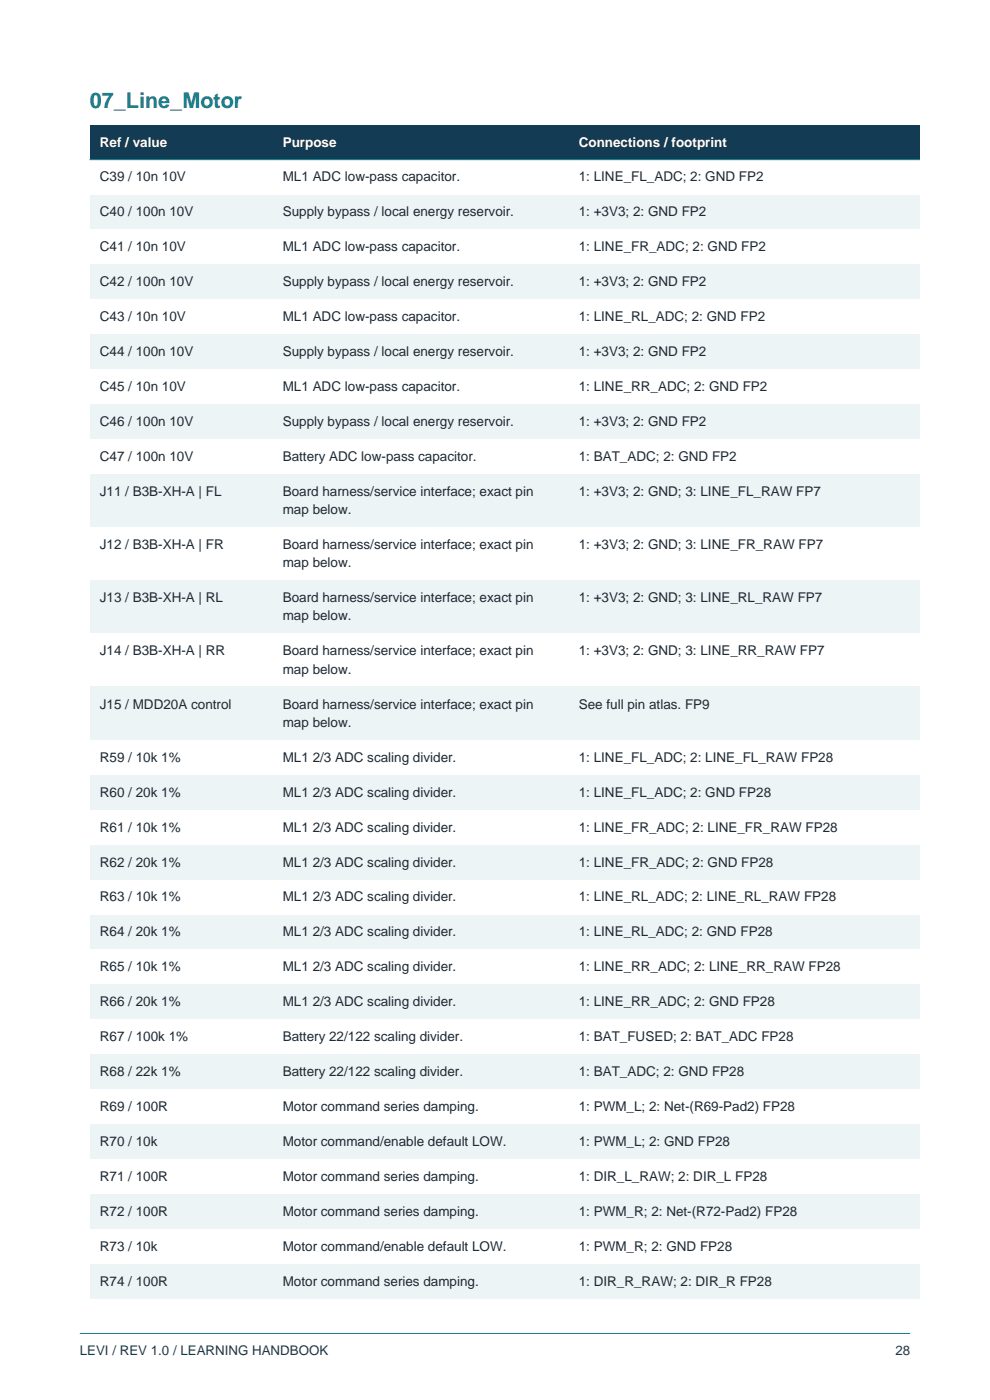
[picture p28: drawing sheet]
<svg xmlns="http://www.w3.org/2000/svg" width="210mm" height="297mm" viewBox="0 0 210 297" stroke-linecap="round" stroke-linejoin="round" font-family="sans-serif">
<defs><g id="words">
<text font-size="4.6" fill="#087f8c" x="19" y="22.9">07_Line_Motor</text>
<g font-size="2.9" fill="#fff">
<text x="21.2" y="31.1">Ref / value</text>
<text x="60" y="31.1">Purpose</text>
<text x="122.8" y="31.1">Connections / footprint</text>
</g>
<g font-size="2.9" fill="#1f2933">
<text x="21.2" y="38.5">C39 / 10n 10V</text>
<text x="60" y="38.5">ML1 ADC low-pass capacitor.</text>
<text x="122.8" y="38.5">1: LINE_FL_ADC; 2: GND FP2</text>
<text x="21.2" y="45.9">C40 / 100n 10V</text>
<text x="60" y="45.9">Supply bypass / local energy reservoir.</text>
<text x="122.8" y="45.9">1: +3V3; 2: GND FP2</text>
<text x="21.2" y="53.3">C41 / 10n 10V</text>
<text x="60" y="53.3">ML1 ADC low-pass capacitor.</text>
<text x="122.8" y="53.3">1: LINE_FR_ADC; 2: GND FP2</text>
<text x="21.2" y="60.7">C42 / 100n 10V</text>
<text x="60" y="60.7">Supply bypass / local energy reservoir.</text>
<text x="122.8" y="60.7">1: +3V3; 2: GND FP2</text>
<text x="21.2" y="68.1">C43 / 10n 10V</text>
<text x="60" y="68.1">ML1 ADC low-pass capacitor.</text>
<text x="122.8" y="68.1">1: LINE_RL_ADC; 2: GND FP2</text>
<text x="21.2" y="75.5">C44 / 100n 10V</text>
<text x="60" y="75.5">Supply bypass / local energy reservoir.</text>
<text x="122.8" y="75.5">1: +3V3; 2: GND FP2</text>
<text x="21.2" y="82.9">C45 / 10n 10V</text>
<text x="60" y="82.9">ML1 ADC low-pass capacitor.</text>
<text x="122.8" y="82.9">1: LINE_RR_ADC; 2: GND FP2</text>
<text x="21.2" y="90.3">C46 / 100n 10V</text>
<text x="60" y="90.3">Supply bypass / local energy reservoir.</text>
<text x="122.8" y="90.3">1: +3V3; 2: GND FP2</text>
<text x="21.2" y="97.8">C47 / 100n 10V</text>
<text x="60" y="97.8">Battery ADC low-pass capacitor.</text>
<text x="122.8" y="97.8">1: BAT_ADC; 2: GND FP2</text>
<text x="21.2" y="105.2">J11 / B3B-XH-A | FL</text>
<text x="60" y="105.2">Board harness/service interface; exact pin</text>
<text x="122.8" y="105.2">1: +3V3; 2: GND; 3: LINE_FL_RAW FP7</text>
<text x="60" y="109">map below.</text>
<text x="21.2" y="116.5">J12 / B3B-XH-A | FR</text>
<text x="60" y="116.5">Board harness/service interface; exact pin</text>
<text x="122.8" y="116.5">1: +3V3; 2: GND; 3: LINE_FR_RAW FP7</text>
<text x="60" y="120.3">map below.</text>
<text x="21.2" y="127.7">J13 / B3B-XH-A | RL</text>
<text x="60" y="127.7">Board harness/service interface; exact pin</text>
<text x="60" y="131.6">map below.</text>
<text x="122.8" y="127.7">1: +3V3; 2: GND; 3: LINE_RL_RAW FP7</text>
<text x="21.2" y="139">J14 / B3B-XH-A | RR</text>
<text x="60" y="139">Board harness/service interface; exact pin</text>
<text x="60" y="142.9">map below.</text>
<text x="122.8" y="139">1: +3V3; 2: GND; 3: LINE_RR_RAW FP7</text>
<text x="21.2" y="150.3">J15 / MDD20A control</text>
<text x="60" y="150.3">Board harness/service interface; exact pin</text>
<text x="60" y="154.2">map below.</text>
<text x="122.8" y="150.3">See full pin atlas. FP9</text>
<text x="21.2" y="161.6">R59 / 10k 1%</text>
<text x="60" y="161.6">ML1 2/3 ADC scaling divider.</text>
<text x="122.8" y="161.6">1: LINE_FL_ADC; 2: LINE_FL_RAW FP28</text>
<text x="21.2" y="169">R60 / 20k 1%</text>
<text x="60" y="169">ML1 2/3 ADC scaling divider.</text>
<text x="122.8" y="169">1: LINE_FL_ADC; 2: GND FP28</text>
<text x="21.2" y="176.4">R61 / 10k 1%</text>
<text x="60" y="176.4">ML1 2/3 ADC scaling divider.</text>
<text x="122.8" y="176.4">1: LINE_FR_ADC; 2: LINE_FR_RAW FP28</text>
<text x="21.2" y="183.8">R62 / 20k 1%</text>
<text x="60" y="183.8">ML1 2/3 ADC scaling divider.</text>
<text x="122.8" y="183.8">1: LINE_FR_ADC; 2: GND FP28</text>
<text x="21.2" y="191.2">R63 / 10k 1%</text>
<text x="60" y="191.2">ML1 2/3 ADC scaling divider.</text>
<text x="122.8" y="191.2">1: LINE_RL_ADC; 2: LINE_RL_RAW FP28</text>
<text x="21.2" y="198.6">R64 / 20k 1%</text>
<text x="60" y="198.6">ML1 2/3 ADC scaling divider.</text>
<text x="122.8" y="198.6">1: LINE_RL_ADC; 2: GND FP28</text>
<text x="21.2" y="206.1">R65 / 10k 1%</text>
<text x="60" y="206.1">ML1 2/3 ADC scaling divider.</text>
<text x="122.8" y="206.1">1: LINE_RR_ADC; 2: LINE_RR_RAW FP28</text>
<text x="21.2" y="213.5">R66 / 20k 1%</text>
<text x="60" y="213.5">ML1 2/3 ADC scaling divider.</text>
<text x="122.8" y="213.5">1: LINE_RR_ADC; 2: GND FP28</text>
<text x="21.2" y="220.9">R67 / 100k 1%</text>
<text x="60" y="220.9">Battery 22/122 scaling divider.</text>
<text x="122.8" y="220.9">1: BAT_FUSED; 2: BAT_ADC FP28</text>
<text x="21.2" y="228.3">R68 / 22k 1%</text>
<text x="60" y="228.3">Battery 22/122 scaling divider.</text>
<text x="122.8" y="228.3">1: BAT_ADC; 2: GND FP28</text>
<text x="21.2" y="235.7">R69 / 100R</text>
<text x="60" y="235.7">Motor command series damping.</text>
<text x="122.8" y="235.7">1: PWM_L; 2: Net-(R69-Pad2) FP28</text>
<text x="21.2" y="243.1">R70 / 10k</text>
<text x="60" y="243.1">Motor command/enable default LOW.</text>
<text x="122.8" y="243.1">1: PWM_L; 2: GND FP28</text>
<text x="21.2" y="250.5">R71 / 100R</text>
<text x="60" y="250.5">Motor command series damping.</text>
<text x="122.8" y="250.5">1: DIR_L_RAW; 2: DIR_L FP28</text>
<text x="21.2" y="257.9">R72 / 100R</text>
<text x="60" y="257.9">Motor command series damping.</text>
<text x="122.8" y="257.9">1: PWM_R; 2: Net-(R72-Pad2) FP28</text>
<text x="21.2" y="265.3">R73 / 10k</text>
<text x="60" y="265.3">Motor command/enable default LOW.</text>
<text x="122.8" y="265.3">1: PWM_R; 2: GND FP28</text>
<text x="21.2" y="272.7">R74 / 100R</text>
<text x="60" y="272.7">Motor command series damping.</text>
<text x="122.8" y="272.7">1: DIR_R_RAW; 2: DIR_R FP28</text>
</g>
<g font-size="2.8" fill="#133b53">
<text x="16.9" y="287.5">LEVI / REV 1.0 / LEARNING HANDBOOK</text>
<text x="189.9" y="287.5">28</text>
</g>
</g></defs>
<path d="M16.9 282.9h176.2" fill="none" stroke="#087f8c" stroke-width=".21"/>
<path d="M19 26.5h176.1v7.4h-176.1z" fill-rule="evenodd" fill="#133b53"/>
<path d="M19 33.9h176.1v7.4h-176.1z" fill-rule="evenodd" fill="#fff"/>
<path d="M19 41.3h176.1v7.4h-176.1z" fill-rule="evenodd" fill="#edf4f6"/>
<path d="M19 48.7h176.1v7.4h-176.1z" fill-rule="evenodd" fill="#fff"/>
<path d="M19 56.1h176.1v7.4h-176.1z" fill-rule="evenodd" fill="#edf4f6"/>
<path d="M19 63.5h176.1v7.4h-176.1z" fill-rule="evenodd" fill="#fff"/>
<path d="M19 70.9h176.1v7.4h-176.1z" fill-rule="evenodd" fill="#edf4f6"/>
<path d="M19 78.3h176.1v7.4h-176.1z" fill-rule="evenodd" fill="#fff"/>
<path d="M19 85.7h176.1v7.4h-176.1z" fill-rule="evenodd" fill="#edf4f6"/>
<path d="M19 93.1h176.1v7.4h-176.1z" fill-rule="evenodd" fill="#fff"/>
<path d="M19 100.5h176.1v11.3h-176.1z" fill-rule="evenodd" fill="#edf4f6"/>
<path d="M19 111.8h176.1v11.3h-176.1z" fill-rule="evenodd" fill="#fff"/>
<path d="M19 123.1h176.1v11.3h-176.1z" fill-rule="evenodd" fill="#edf4f6"/>
<path d="M19 134.4h176.1v11.3h-176.1z" fill-rule="evenodd" fill="#fff"/>
<path d="M19 145.7h176.1v11.3h-176.1z" fill-rule="evenodd" fill="#edf4f6"/>
<path d="M19 157h176.1v7.4h-176.1z" fill-rule="evenodd" fill="#fff"/>
<path d="M19 164.4h176.1v7.4h-176.1z" fill-rule="evenodd" fill="#edf4f6"/>
<path d="M19 171.8h176.1v7.4h-176.1z" fill-rule="evenodd" fill="#fff"/>
<path d="M19 179.2h176.1v7.4h-176.1z" fill-rule="evenodd" fill="#edf4f6"/>
<path d="M19 186.6h176.1v7.4h-176.1z" fill-rule="evenodd" fill="#fff"/>
<path d="M19 194h176.1v7.4h-176.1z" fill-rule="evenodd" fill="#edf4f6"/>
<path d="M19 201.4h176.1v7.4h-176.1z" fill-rule="evenodd" fill="#fff"/>
<path d="M19 208.8h176.1v7.5h-176.1z" fill-rule="evenodd" fill="#edf4f6"/>
<path d="M19 216.3h176.1v7.4h-176.1z" fill-rule="evenodd" fill="#fff"/>
<path d="M19 223.7h176.1v7.4h-176.1z" fill-rule="evenodd" fill="#edf4f6"/>
<path d="M19 231.1h176.1v7.4h-176.1z" fill-rule="evenodd" fill="#fff"/>
<path d="M19 238.5h176.1v7.4h-176.1z" fill-rule="evenodd" fill="#edf4f6"/>
<path d="M19 245.9h176.1v7.4h-176.1z" fill-rule="evenodd" fill="#fff"/>
<path d="M19 253.3h176.1v7.4h-176.1z" fill-rule="evenodd" fill="#edf4f6"/>
<path d="M19 260.7h176.1v7.4h-176.1z" fill-rule="evenodd" fill="#fff"/>
<path d="M19 268.1h176.1v7.4h-176.1z" fill-rule="evenodd" fill="#edf4f6"/>
<path d="M19 33.9h176.1" fill="none" stroke="#087f8c" stroke-width=".21"/>
<use href="#words"/>
</svg>
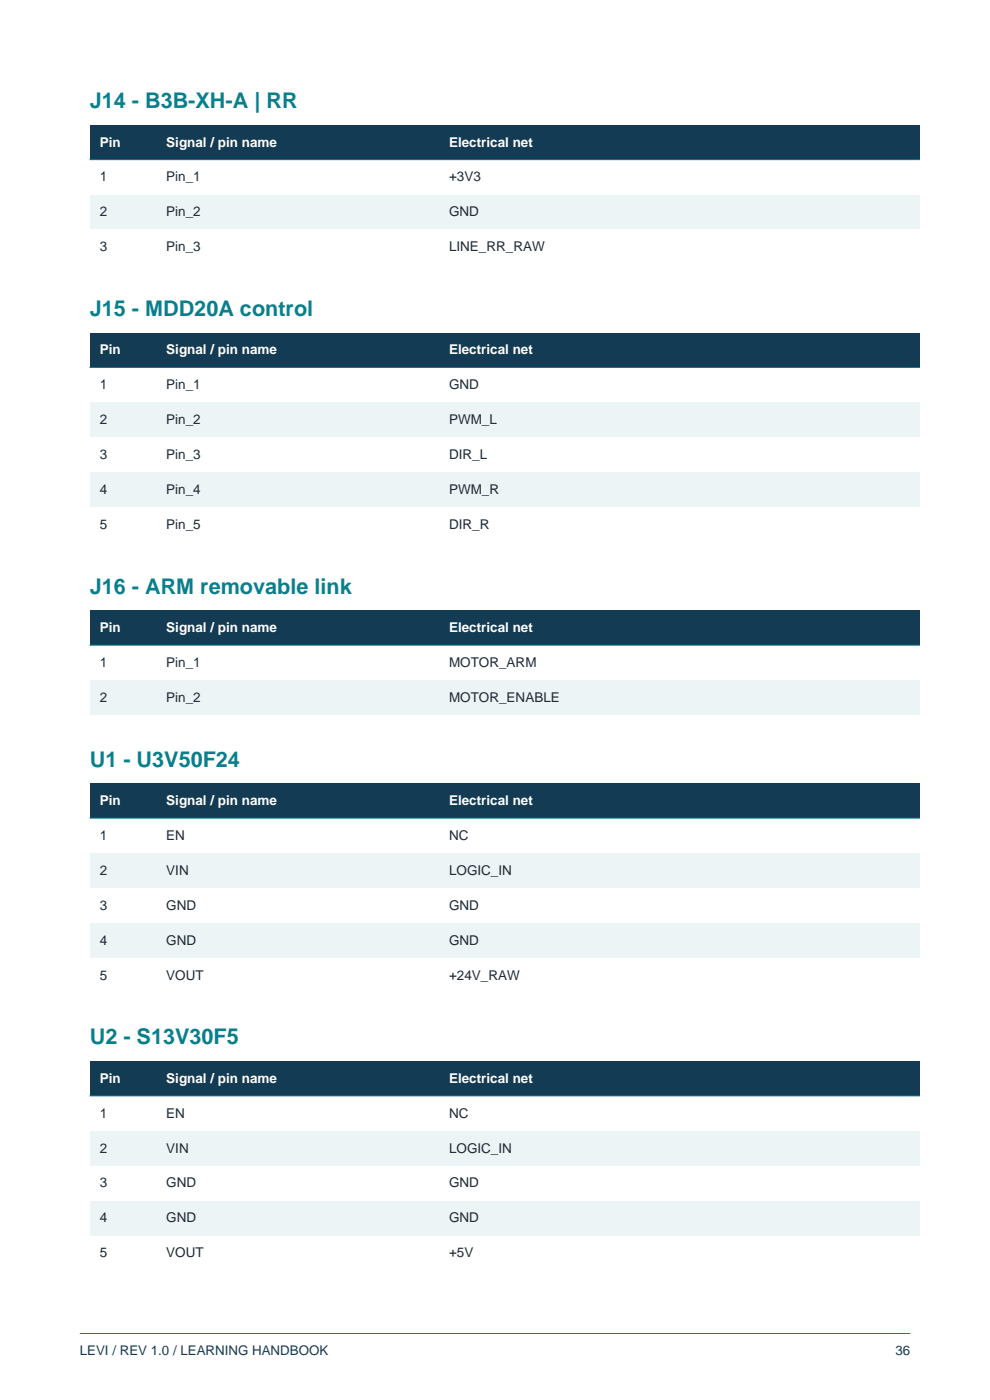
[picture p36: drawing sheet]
<svg xmlns="http://www.w3.org/2000/svg" width="210mm" height="297mm" viewBox="0 0 210 297" stroke-linecap="round" stroke-linejoin="round" font-family="sans-serif">
<defs><g id="words">
<g font-size="4.6" fill="#087f8c">
<text x="19" y="22.9">J14 - B3B-XH-A | RR</text>
<text x="19" y="67">J15 - MDD20A control</text>
<text x="19" y="125.9">J16 - ARM removable link</text>
<text x="19" y="162.6">U1 - U3V50F24</text>
<text x="19" y="221.5">U2 - S13V30F5</text>
</g>
<g font-size="2.9" fill="#fff">
<text x="21.2" y="31.1">Pin</text>
<text x="35.3" y="31.1">Signal / pin name</text>
<text x="95.2" y="31.1">Electrical net</text>
<text x="21.2" y="75.2">Pin</text>
<text x="35.3" y="75.2">Signal / pin name</text>
<text x="95.2" y="75.2">Electrical net</text>
<text x="21.2" y="134.1">Pin</text>
<text x="35.3" y="134.1">Signal / pin name</text>
<text x="95.2" y="134.1">Electrical net</text>
<text x="21.2" y="170.8">Pin</text>
<text x="35.3" y="170.8">Signal / pin name</text>
<text x="95.2" y="170.8">Electrical net</text>
<text x="21.2" y="229.7">Pin</text>
<text x="35.3" y="229.7">Signal / pin name</text>
<text x="95.2" y="229.7">Electrical net</text>
</g>
<g font-size="2.9" fill="#1f2933">
<text x="21.2" y="38.5">1</text>
<text x="35.3" y="38.5">Pin_1</text>
<text x="95.2" y="38.5">+3V3</text>
<text x="21.2" y="45.9">2</text>
<text x="35.3" y="45.9">Pin_2</text>
<text x="95.2" y="45.9">GND</text>
<text x="21.2" y="53.3">3</text>
<text x="35.3" y="53.3">Pin_3</text>
<text x="95.2" y="53.3">LINE_RR_RAW</text>
<text x="21.2" y="82.6">1</text>
<text x="35.3" y="82.6">Pin_1</text>
<text x="95.2" y="82.6">GND</text>
<text x="21.2" y="90">2</text>
<text x="35.3" y="90">Pin_2</text>
<text x="95.2" y="90">PWM_L</text>
<text x="21.2" y="97.4">3</text>
<text x="35.3" y="97.4">Pin_3</text>
<text x="95.2" y="97.4">DIR_L</text>
<text x="21.2" y="104.8">4</text>
<text x="35.3" y="104.8">Pin_4</text>
<text x="95.2" y="104.8">PWM_R</text>
<text x="21.2" y="112.2">5</text>
<text x="35.3" y="112.2">Pin_5</text>
<text x="95.2" y="112.2">DIR_R</text>
<text x="21.2" y="141.5">1</text>
<text x="35.3" y="141.5">Pin_1</text>
<text x="95.2" y="141.5">MOTOR_ARM</text>
<text x="21.2" y="148.9">2</text>
<text x="35.3" y="148.9">Pin_2</text>
<text x="95.2" y="148.9">MOTOR_ENABLE</text>
<text x="21.2" y="178.2">1</text>
<text x="35.3" y="178.2">EN</text>
<text x="95.2" y="178.2">NC</text>
<text x="21.2" y="185.6">2</text>
<text x="35.3" y="185.6">VIN</text>
<text x="95.2" y="185.6">LOGIC_IN</text>
<text x="21.2" y="193">3</text>
<text x="35.3" y="193">GND</text>
<text x="95.2" y="193">GND</text>
<text x="21.2" y="200.4">4</text>
<text x="35.3" y="200.4">GND</text>
<text x="95.2" y="200.4">GND</text>
<text x="21.2" y="207.8">5</text>
<text x="35.3" y="207.8">VOUT</text>
<text x="95.2" y="207.8">+24V_RAW</text>
<text x="21.2" y="237.1">1</text>
<text x="35.3" y="237.1">EN</text>
<text x="95.2" y="237.1">NC</text>
<text x="21.2" y="244.5">2</text>
<text x="35.3" y="244.5">VIN</text>
<text x="95.2" y="244.5">LOGIC_IN</text>
<text x="21.2" y="251.9">3</text>
<text x="35.3" y="251.9">GND</text>
<text x="95.2" y="251.9">GND</text>
<text x="21.2" y="259.3">4</text>
<text x="35.3" y="259.3">GND</text>
<text x="95.2" y="259.3">GND</text>
<text x="21.2" y="266.7">5</text>
<text x="35.3" y="266.7">VOUT</text>
<text x="95.2" y="266.7">+5V</text>
</g>
<g font-size="2.8" fill="#133b53">
<text x="16.9" y="287.5">LEVI / REV 1.0 / LEARNING HANDBOOK</text>
<text x="189.9" y="287.5">36</text>
</g>
</g></defs>
<path d="M16.9 282.9h176.2" fill="none" stroke="#087f8c" stroke-width=".21"/>
<path d="M19 26.5h176.1v7.4h-176.1z" fill-rule="evenodd" fill="#133b53"/>
<path d="M19 33.9h176.1v7.4h-176.1z" fill-rule="evenodd" fill="#fff"/>
<path d="M19 41.3h176.1v7.4h-176.1z" fill-rule="evenodd" fill="#edf4f6"/>
<path d="M19 48.7h176.1v7.4h-176.1z" fill-rule="evenodd" fill="#fff"/>
<path d="M19 33.9h176.1" fill="none" stroke="#087f8c" stroke-width=".21"/>
<path d="M19 70.6h176.1v7.4h-176.1z" fill-rule="evenodd" fill="#133b53"/>
<path d="M19 78h176.1v7.4h-176.1z" fill-rule="evenodd" fill="#fff"/>
<path d="M19 85.4h176.1v7.4h-176.1z" fill-rule="evenodd" fill="#edf4f6"/>
<path d="M19 92.8h176.1v7.4h-176.1z" fill-rule="evenodd" fill="#fff"/>
<path d="M19 100.2h176.1v7.4h-176.1z" fill-rule="evenodd" fill="#edf4f6"/>
<path d="M19 107.6h176.1v7.4h-176.1z" fill-rule="evenodd" fill="#fff"/>
<path d="M19 78h176.1" fill="none" stroke="#087f8c" stroke-width=".21"/>
<path d="M19 129.5h176.1v7.4h-176.1z" fill-rule="evenodd" fill="#133b53"/>
<path d="M19 136.9h176.1v7.4h-176.1z" fill-rule="evenodd" fill="#fff"/>
<path d="M19 144.3h176.1v7.4h-176.1z" fill-rule="evenodd" fill="#edf4f6"/>
<path d="M19 136.9h176.1" fill="none" stroke="#087f8c" stroke-width=".21"/>
<path d="M19 166.2h176.1v7.4h-176.1z" fill-rule="evenodd" fill="#133b53"/>
<path d="M19 173.6h176.1v7.4h-176.1z" fill-rule="evenodd" fill="#fff"/>
<path d="M19 181h176.1v7.4h-176.1z" fill-rule="evenodd" fill="#edf4f6"/>
<path d="M19 188.4h176.1v7.4h-176.1z" fill-rule="evenodd" fill="#fff"/>
<path d="M19 195.8h176.1v7.4h-176.1z" fill-rule="evenodd" fill="#edf4f6"/>
<path d="M19 203.2h176.1v7.4h-176.1z" fill-rule="evenodd" fill="#fff"/>
<path d="M19 173.6h176.1" fill="none" stroke="#087f8c" stroke-width=".21"/>
<path d="M19 225.1h176.1v7.4h-176.1z" fill-rule="evenodd" fill="#133b53"/>
<path d="M19 232.5h176.1v7.4h-176.1z" fill-rule="evenodd" fill="#fff"/>
<path d="M19 239.9h176.1v7.4h-176.1z" fill-rule="evenodd" fill="#edf4f6"/>
<path d="M19 247.3h176.1v7.4h-176.1z" fill-rule="evenodd" fill="#fff"/>
<path d="M19 254.7h176.1v7.4h-176.1z" fill-rule="evenodd" fill="#edf4f6"/>
<path d="M19 262.1h176.1v7.4h-176.1z" fill-rule="evenodd" fill="#fff"/>
<path d="M19 232.5h176.1" fill="none" stroke="#087f8c" stroke-width=".21"/>
<use href="#words"/>
</svg>
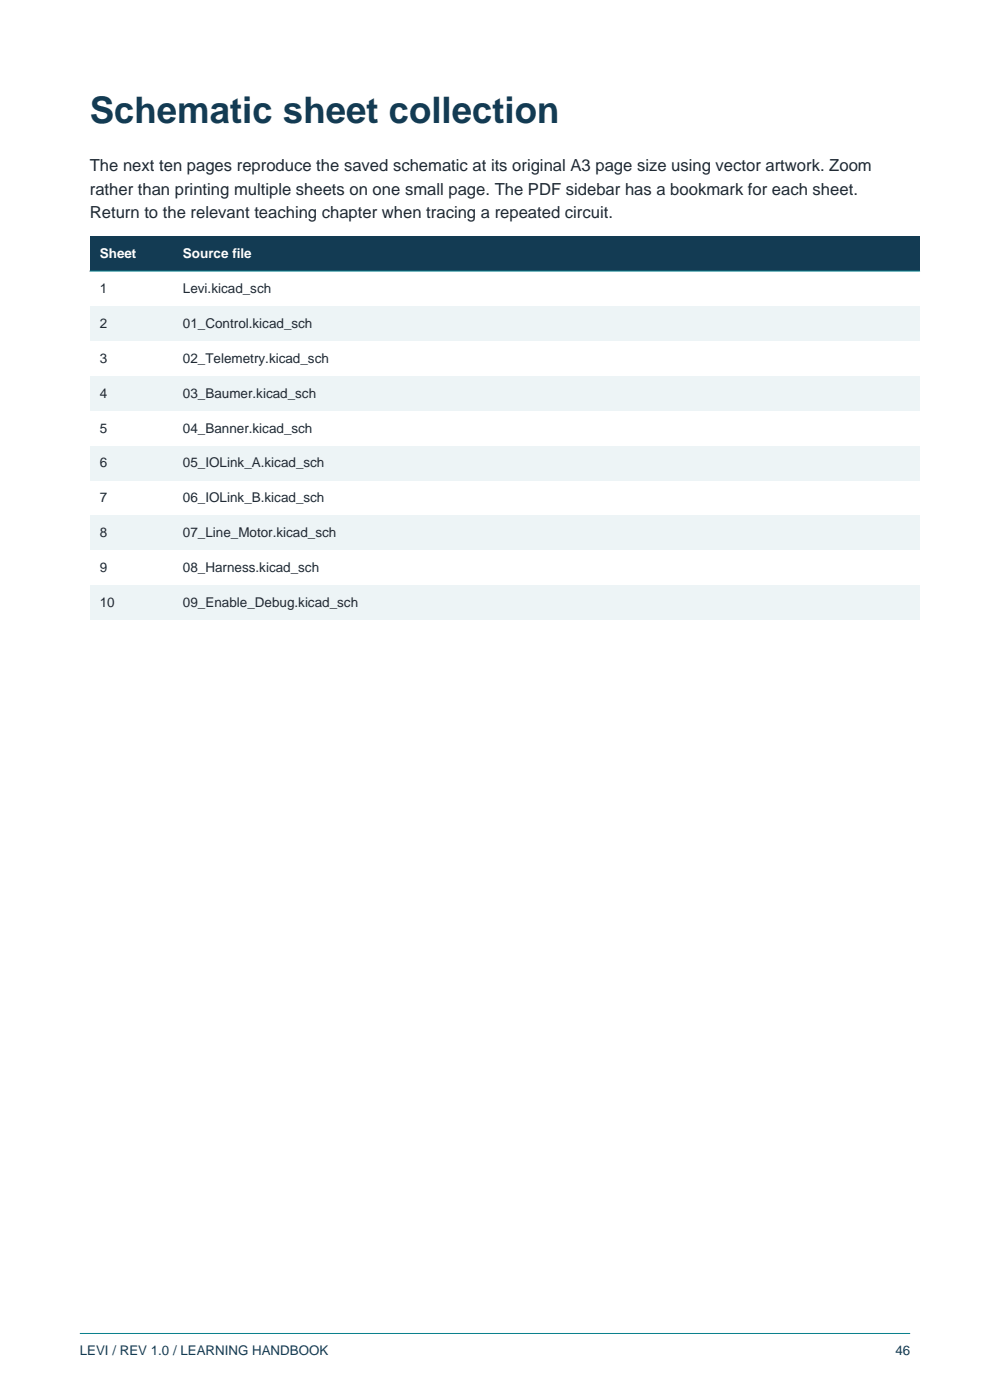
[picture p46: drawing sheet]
<svg xmlns="http://www.w3.org/2000/svg" width="210mm" height="297mm" viewBox="0 0 210 297" stroke-linecap="round" stroke-linejoin="round" font-family="sans-serif">
<defs><g id="words">
<text font-size="7.8" fill="#133b53" x="19" y="26.1">Schematic sheet collection</text>
<g font-size="3.5" fill="#1f2933">
<text x="19" y="36.3">The next ten pages reproduce the saved schematic at its original A3 page size using vector artwork. Zoom</text>
<text x="19" y="41.3">rather than printing multiple sheets on one small page. The PDF sidebar has a bookmark for each sheet.</text>
<text x="19" y="46.2">Return to the relevant teaching chapter when tracing a repeated circuit.</text>
</g>
<g font-size="2.9" fill="#fff">
<text x="21.2" y="54.7">Sheet</text>
<text x="38.8" y="54.7">Source file</text>
</g>
<g font-size="2.9" fill="#1f2933">
<text x="21.2" y="62.1">1</text>
<text x="38.8" y="62.1">Levi.kicad_sch</text>
<text x="21.2" y="69.5">2</text>
<text x="38.8" y="69.5">01_Control.kicad_sch</text>
<text x="21.2" y="76.9">3</text>
<text x="38.8" y="76.9">02_Telemetry.kicad_sch</text>
<text x="21.2" y="84.3">4</text>
<text x="38.8" y="84.3">03_Baumer.kicad_sch</text>
<text x="21.2" y="91.8">5</text>
<text x="38.8" y="91.8">04_Banner.kicad_sch</text>
<text x="21.2" y="99.2">6</text>
<text x="38.8" y="99.2">05_IOLink_A.kicad_sch</text>
<text x="21.2" y="106.6">7</text>
<text x="38.8" y="106.6">06_IOLink_B.kicad_sch</text>
<text x="21.2" y="114">8</text>
<text x="38.8" y="114">07_Line_Motor.kicad_sch</text>
<text x="21.2" y="121.4">9</text>
<text x="38.8" y="121.4">08_Harness.kicad_sch</text>
<text x="21.2" y="128.8">10</text>
<text x="38.8" y="128.8">09_Enable_Debug.kicad_sch</text>
</g>
<g font-size="2.8" fill="#133b53">
<text x="16.9" y="287.5">LEVI / REV 1.0 / LEARNING HANDBOOK</text>
<text x="189.9" y="287.5">46</text>
</g>
</g></defs>
<path d="M16.9 282.9h176.2" fill="none" stroke="#087f8c" stroke-width=".21"/>
<path d="M19 50.1h176.1v7.4h-176.1z" fill-rule="evenodd" fill="#133b53"/>
<path d="M19 57.5h176.1v7.4h-176.1z" fill-rule="evenodd" fill="#fff"/>
<path d="M19 64.9h176.1v7.4h-176.1z" fill-rule="evenodd" fill="#edf4f6"/>
<path d="M19 72.3h176.1v7.4h-176.1z" fill-rule="evenodd" fill="#fff"/>
<path d="M19 79.7h176.1v7.4h-176.1z" fill-rule="evenodd" fill="#edf4f6"/>
<path d="M19 87.1h176.1v7.4h-176.1z" fill-rule="evenodd" fill="#fff"/>
<path d="M19 94.5h176.1v7.5h-176.1z" fill-rule="evenodd" fill="#edf4f6"/>
<path d="M19 102h176.1v7.4h-176.1z" fill-rule="evenodd" fill="#fff"/>
<path d="M19 109.4h176.1v7.4h-176.1z" fill-rule="evenodd" fill="#edf4f6"/>
<path d="M19 116.8h176.1v7.4h-176.1z" fill-rule="evenodd" fill="#fff"/>
<path d="M19 124.2h176.1v7.4h-176.1z" fill-rule="evenodd" fill="#edf4f6"/>
<path d="M19 57.5h176.1" fill="none" stroke="#087f8c" stroke-width=".21"/>
<use href="#words"/>
</svg>
